VERSION 5.7 ;
  NOWIREEXTENSIONATPIN ON ;
  DIVIDERCHAR "/" ;
  BUSBITCHARS "[]" ;
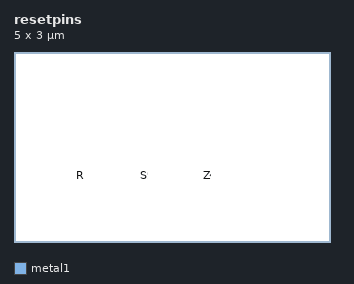
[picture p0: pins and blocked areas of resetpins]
MACRO resetpins
  CLASS BLOCK ;
  FOREIGN resetpins ;
  ORIGIN 0.000 0.000 ;
  SIZE 5.000 BY 3.000 ;
  PIN R
    DIRECTION INPUT ;
    USE  ;
    PORT
      LAYER metal1 ;
        RECT 1.000 1.000 1.100 1.100 ;
    END
  END R
  PIN S
    DIRECTION INPUT ;
    USE  ;
    PORT
      LAYER metal1 ;
        RECT 2.000 1.000 2.100 1.100 ;
    END
  END S
  PIN Z
    DIRECTION OUTPUT ;
    USE  ;
    PORT
      LAYER metal1 ;
        RECT 3.000 1.000 3.100 1.100 ;
    END
  END Z
END resetpins
END LIBRARY

